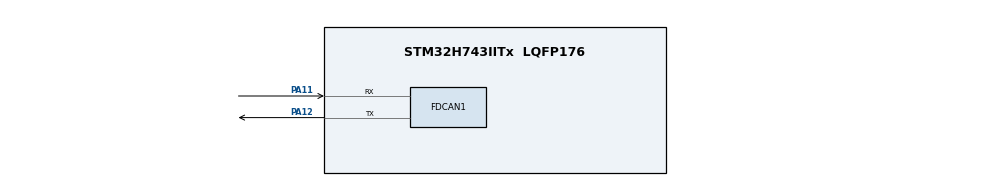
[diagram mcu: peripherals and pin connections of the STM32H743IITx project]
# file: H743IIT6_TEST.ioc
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CORTEX_M7.default_mode_Activation=1
FDCAN1.CalculateBaudRateNominal=650000
FDCAN1.CalculateTimeBitNominal=1538
FDCAN1.CalculateTimeQuantumNominal=19.23076923076923
FDCAN1.DataSyncJumpWidth=2
FDCAN1.DataTimeSeg1=13
FDCAN1.DataTimeSeg2=2
FDCAN1.ExtFiltersNbr=4
FDCAN1.MessageRAMOffset=0x812
FDCAN1.NominalPrescaler=1
FDCAN1.NominalSyncJumpWidth=20
FDCAN1.NominalTimeSeg1=59
FDCAN1.NominalTimeSeg2=20
FDCAN1.RxBuffersNbr=2
FDCAN1.RxFifo0ElmtsNbr=8
FDCAN1.RxFifo1ElmtsNbr=8
FDCAN1.StdFiltersNbr=4
FDCAN1.TxBuffersNbr=8
FDCAN1.TxEventsNbr=8
FDCAN1.TxFifoQueueElmtsNbr=8
Mcu.Family=STM32H7
Mcu.Name=STM32H743IITx
Mcu.Package=LQFP176
NVIC.PriorityGroup=NVIC_PRIORITYGROUP_4
PA11.Mode=FDCAN_Activate
PA11.Signal=FDCAN1_RX
PA12.Mode=FDCAN_Activate
PA12.Signal=FDCAN1_TX
PA13\ (JTMS/SWDIO).Mode=Serial_Wire
PA13\ (JTMS/SWDIO).Signal=DEBUG_JTMS-SWDIO
PA14\ (JTCK/SWCLK).Mode=Serial_Wire
PA14\ (JTCK/SWCLK).Signal=DEBUG_JTCK-SWCLK
PH0-OSC_IN\ (PH0).Mode=HSE-External-Oscillator
PH0-OSC_IN\ (PH0).Signal=RCC_OSC_IN
PH1-OSC_OUT\ (PH1).Mode=HSE-External-Oscillator
PH1-OSC_OUT\ (PH1).Signal=RCC_OSC_OUT
ProjectManager.HeapSize=0x200
ProjectManager.StackSize=0x400
ProjectManager.TargetToolchain=MDK-ARM V5.32
RCC.ADCFreq_Value=48375000
RCC.APB1Freq_Value=78000000
RCC.APB2Freq_Value=78000000
RCC.APB3Freq_Value=78000000
RCC.APB4Freq_Value=78000000
RCC.CortexFreq_Value=78000000
RCC.DIVM1=2
RCC.DIVN1=13
RCC.DIVQ1=3
RCC.HCLKFreq_Value=78000000
RCC.HSE_VALUE=24000000
RCC.PLL2FRACN=0
RCC.PLL3FRACN=0
RCC.PLLFRACN=0
RCC.PLLSourceVirtual=RCC_PLLSOURCE_HSE
RCC.SYSCLKFreq_VALUE=78000000
RCC.SYSCLKSource=RCC_SYSCLKSOURCE_PLLCLK
RCC.USBFreq_Value=52000000
VP_MEMORYMAP_VS_MEMORYMAP.Mode=CurAppReg
board=custom

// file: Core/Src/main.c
/* USER CODE BEGIN Header */
/**
  ******************************************************************************
  * @file           : main.c
  * @brief          : Main program body
  ******************************************************************************
  * @attention
  *
  * Copyright (c) 2025 STMicroelectronics.
  * All rights reserved.
  *
  * This software is licensed under terms that can be found in the LICENSE file
  * in the root directory of this software component.
  * If no LICENSE file comes with this software, it is provided AS-IS.
  *
  ******************************************************************************
  */
/* USER CODE END Header */
#include "main.h"
#include "fdcan.h"
#include "memorymap.h"
#include "gpio.h"

/* USER CODE BEGIN Includes */
#include "bsp_fdcan.h"
/* USER CODE END Includes */

void SystemClock_Config(void);
static void MPU_Config(void);

/* USER CODE BEGIN 0 */
uint8_t tx_data[8] = {0,1,2,3,4,5,6,7};
/* USER CODE END 0 */

int main(void)
{

  /* MPU Configuration--------------------------------------------------------*/
  MPU_Config();

  /* MCU Configuration--------------------------------------------------------*/

  /* Reset of all peripherals, Initializes the Flash interface and the Systick. */
  HAL_Init();

  /* Configure the system clock */
  SystemClock_Config();

  /* Initialize all configured peripherals */
  MX_GPIO_Init();
  MX_FDCAN1_Init();
  /* USER CODE BEGIN 2 */
	bsp_can_init();
  /* USER CODE END 2 */

  /* Infinite loop */
  /* USER CODE BEGIN WHILE */
  while (1)
  {
		fdcanx_send_data(&hfdcan1, 0x520, tx_data, 8);
		HAL_Delay(100);

//		fdcanx_send_data(&hfdcan2, 0x520, tx_data, 8);
//		HAL_Delay(100);
//
//		fdcanx_send_data(&hfdcan3, 0x520, tx_data, 8);
//		HAL_Delay(100);
    /* USER CODE END WHILE */

  }
}

void SystemClock_Config(void)
{
  RCC_OscInitTypeDef RCC_OscInitStruct = {0};
  RCC_ClkInitTypeDef RCC_ClkInitStruct = {0};

  /** Supply configuration update enable
  */
  HAL_PWREx_ConfigSupply(PWR_LDO_SUPPLY);

  /** Configure the main internal regulator output voltage
  */
  __HAL_PWR_VOLTAGESCALING_CONFIG(PWR_REGULATOR_VOLTAGE_SCALE3);

  while(!__HAL_PWR_GET_FLAG(PWR_FLAG_VOSRDY)) {}

  /** Initializes the RCC Oscillators according to the specified parameters
  * in the RCC_OscInitTypeDef structure.
  */
  RCC_OscInitStruct.OscillatorType = RCC_OSCILLATORTYPE_HSE;
  RCC_OscInitStruct.HSEState = RCC_HSE_ON;
  RCC_OscInitStruct.PLL.PLLState = RCC_PLL_ON;
  RCC_OscInitStruct.PLL.PLLSource = RCC_PLLSOURCE_HSE;
  RCC_OscInitStruct.PLL.PLLM = 1;
  RCC_OscInitStruct.PLL.PLLN = 10;
  RCC_OscInitStruct.PLL.PLLP = 2;
  RCC_OscInitStruct.PLL.PLLQ = 2;
  RCC_OscInitStruct.PLL.PLLR = 2;
  RCC_OscInitStruct.PLL.PLLRGE = RCC_PLL1VCIRANGE_3;
  RCC_OscInitStruct.PLL.PLLVCOSEL = RCC_PLL1VCOMEDIUM;
  RCC_OscInitStruct.PLL.PLLFRACN = 0;
  if (HAL_RCC_OscConfig(&RCC_OscInitStruct) != HAL_OK)
  {
    Error_Handler();
  }

  /** Initializes the CPU, AHB and APB buses clocks
  */
  RCC_ClkInitStruct.ClockType = RCC_CLOCKTYPE_HCLK|RCC_CLOCKTYPE_SYSCLK
                              |RCC_CLOCKTYPE_PCLK1|RCC_CLOCKTYPE_PCLK2
                              |RCC_CLOCKTYPE_D3PCLK1|RCC_CLOCKTYPE_D1PCLK1;
  RCC_ClkInitStruct.SYSCLKSource = RCC_SYSCLKSOURCE_PLLCLK;
  RCC_ClkInitStruct.SYSCLKDivider = RCC_SYSCLK_DIV1;
  RCC_ClkInitStruct.AHBCLKDivider = RCC_HCLK_DIV1;
  RCC_ClkInitStruct.APB3CLKDivider = RCC_APB3_DIV1;
  RCC_ClkInitStruct.APB1CLKDivider = RCC_APB1_DIV1;
  RCC_ClkInitStruct.APB2CLKDivider = RCC_APB2_DIV1;
  RCC_ClkInitStruct.APB4CLKDivider = RCC_APB4_DIV1;

  if (HAL_RCC_ClockConfig(&RCC_ClkInitStruct, FLASH_LATENCY_1) != HAL_OK)
  {
    Error_Handler();
  }
}

 /* MPU Configuration */

void MPU_Config(void)
{
  MPU_Region_InitTypeDef MPU_InitStruct = {0};

  /* Disables the MPU */
  HAL_MPU_Disable();

  /** Initializes and configures the Region and the memory to be protected
  */
  MPU_InitStruct.Enable = MPU_REGION_ENABLE;
  MPU_InitStruct.Number = MPU_REGION_NUMBER0;
  MPU_InitStruct.BaseAddress = 0x0;
  MPU_InitStruct.Size = MPU_REGION_SIZE_4GB;
  MPU_InitStruct.SubRegionDisable = 0x87;
  MPU_InitStruct.TypeExtField = MPU_TEX_LEVEL0;
  MPU_InitStruct.AccessPermission = MPU_REGION_NO_ACCESS;
  MPU_InitStruct.DisableExec = MPU_INSTRUCTION_ACCESS_DISABLE;
  MPU_InitStruct.IsShareable = MPU_ACCESS_SHAREABLE;
  MPU_InitStruct.IsCacheable = MPU_ACCESS_NOT_CACHEABLE;
  MPU_InitStruct.IsBufferable = MPU_ACCESS_NOT_BUFFERABLE;

  HAL_MPU_ConfigRegion(&MPU_InitStruct);
  /* Enables the MPU */
  HAL_MPU_Enable(MPU_PRIVILEGED_DEFAULT);

}

void Error_Handler(void)
{
  __disable_irq();
  while (1)
  {
  }
}
